VERSION 5.8 ;
BUSBITCHARS "[]" ;
DIVIDERCHAR "/" ;
CLEARANCEMEASURE EUCLIDEAN ;

SITE coresite_DH_P
    SIZE 0.0450 BY 0.2880 ;
    CLASS CORE ;
    SYMMETRY X Y ;
END coresite_DH_P

SITE coresite_DH_N
    SIZE 0.0450 BY 0.2880 ;
    CLASS CORE ;
    SYMMETRY X Y ;
END coresite_DH_N

SITE coresite
    SIZE 0.0450 BY 0.1440 ;
    CLASS CORE ;
    SYMMETRY X Y ;
END coresite

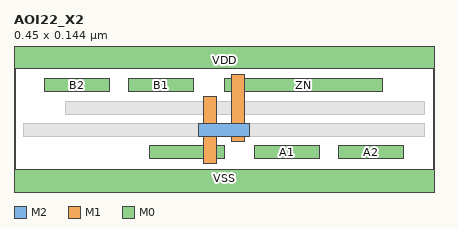
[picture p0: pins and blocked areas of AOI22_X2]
MACRO AOI22_X2
  CLASS CORE ;
  ORIGIN 0 0 ;
  FOREIGN AOI22_X2 0 0 ;
  SIZE 0.4500 BY 0.1440 ;
  SYMMETRY X Y ;
  SITE coresite ;
  PIN ZN
    DIRECTION OUTPUT ;
    USE SIGNAL ;
    PORT
      LAYER M2 ;
        RECT 0.1980 0.0670 0.2520 0.0530 ;
      LAYER M1 ;
        RECT 0.2025 0.0960 0.2175 0.0240 ;
        RECT 0.2325 0.1200 0.2475 0.0480 ;
      LAYER M0 ;
        RECT 0.1455 0.0430 0.2250 0.0290 ;
        RECT 0.2250 0.1150 0.3945 0.1010 ;
    END
  END ZN
  PIN A1
    DIRECTION INPUT ;
    USE SIGNAL ;
    PORT
      LAYER M0 ;
        RECT 0.2580 0.0430 0.3270 0.0290 ;
    END
  END A1
  PIN A2
    DIRECTION INPUT ;
    USE SIGNAL ;
    PORT
      LAYER M0 ;
        RECT 0.3480 0.0430 0.4170 0.0290 ;
    END
  END A2
  PIN B2
    DIRECTION INPUT ;
    USE SIGNAL ;
    PORT
      LAYER M0 ;
        RECT 0.0330 0.1150 0.1020 0.1010 ;
    END
  END B2
  PIN B1
    DIRECTION INPUT ;
    USE SIGNAL ;
    PORT
      LAYER M0 ;
        RECT 0.1230 0.1150 0.1920 0.1010 ;
    END
  END B1
  PIN VDD
    DIRECTION INOUT ;
    USE POWER ;
    SHAPE ABUTMENT ;
    PORT
      LAYER M0 ;
        RECT 0.0000 0.1260 0.4500 0.1620 ;
    END
  END VDD
  PIN VSS
    DIRECTION INOUT ;
    USE GROUND ;
    SHAPE ABUTMENT ;
    PORT
      LAYER M0 ;
        RECT 0.0000 -0.0180 0.4500 0.0180 ;
    END
  END VSS
  OBS
      LAYER V1 ;
        RECT 0.2030 0.0530 0.2170 0.0670 ;
        RECT 0.2330 0.0530 0.2470 0.0670 ;
      LAYER V0 ;
        RECT 0.2030 0.0290 0.2170 0.0430 ;
        RECT 0.2330 0.1010 0.2470 0.1150 ;
      LAYER M0 ;
        RECT 0.0105 0.0530 0.2145 0.0670 ;
        RECT 0.2355 0.0530 0.4395 0.0670 ;
        RECT 0.0555 0.0770 0.4395 0.0910 ;
  END
END AOI22_X2

END LIBRARY
